VERSION 5.8 ;
BUSBITCHARS "[]" ;
DIVIDERCHAR "/" ;
UNITS
    DATABASE MICRONS 1000 ;
END UNITS

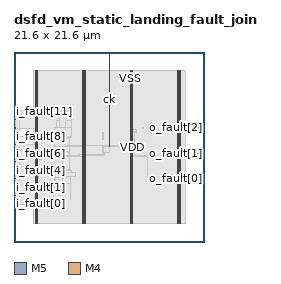
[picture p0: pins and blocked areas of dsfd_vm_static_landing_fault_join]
MACRO dsfd_vm_static_landing_fault_join
  FOREIGN dsfd_vm_static_landing_fault_join 0 0 ;
  CLASS BLOCK ;
  SIZE 21.6 BY 21.6 ;
  PIN ck
    DIRECTION INPUT ;
    USE SIGNAL ;
    PORT
      LAYER M5 ;
        RECT  10.8 21.408 10.824 21.6 ;
    END
    PORT
      LAYER M5 ;
        RECT  10.8 10.883 10.824 21.456 ;
    END
  END ck
  PIN i_fault[0]
    DIRECTION INPUT ;
    USE SIGNAL ;
    PORT
      LAYER M4 ;
        RECT  0 4.32 0.192 4.344 ;
    END
  END i_fault[0]
  PIN i_fault[10]
    DIRECTION INPUT ;
    USE SIGNAL ;
    PORT
      LAYER M4 ;
        RECT  0 13.92 0.192 13.944 ;
    END
  END i_fault[10]
  PIN i_fault[11]
    DIRECTION INPUT ;
    USE SIGNAL ;
    PORT
      LAYER M4 ;
        RECT  0 14.88 0.192 14.904 ;
    END
  END i_fault[11]
  PIN i_fault[1]
    DIRECTION INPUT ;
    USE SIGNAL ;
    PORT
      LAYER M4 ;
        RECT  0 5.28 0.192 5.304 ;
    END
  END i_fault[1]
  PIN i_fault[2]
    DIRECTION INPUT ;
    USE SIGNAL ;
    PORT
      LAYER M4 ;
        RECT  0 6.24 0.192 6.264 ;
    END
  END i_fault[2]
  PIN i_fault[3]
    DIRECTION INPUT ;
    USE SIGNAL ;
    PORT
      LAYER M4 ;
        RECT  0 7.2 0.192 7.224 ;
    END
  END i_fault[3]
  PIN i_fault[4]
    DIRECTION INPUT ;
    USE SIGNAL ;
    PORT
      LAYER M4 ;
        RECT  0 8.16 0.192 8.184 ;
    END
  END i_fault[4]
  PIN i_fault[5]
    DIRECTION INPUT ;
    USE SIGNAL ;
    PORT
      LAYER M4 ;
        RECT  0 9.12 0.192 9.144 ;
    END
  END i_fault[5]
  PIN i_fault[6]
    DIRECTION INPUT ;
    USE SIGNAL ;
    PORT
      LAYER M4 ;
        RECT  0 10.08 0.192 10.104 ;
    END
  END i_fault[6]
  PIN i_fault[7]
    DIRECTION INPUT ;
    USE SIGNAL ;
    PORT
      LAYER M4 ;
        RECT  0 11.04 0.192 11.064 ;
    END
  END i_fault[7]
  PIN i_fault[8]
    DIRECTION INPUT ;
    USE SIGNAL ;
    PORT
      LAYER M4 ;
        RECT  0 12 0.192 12.024 ;
    END
  END i_fault[8]
  PIN i_fault[9]
    DIRECTION INPUT ;
    USE SIGNAL ;
    PORT
      LAYER M4 ;
        RECT  0 12.96 0.192 12.984 ;
    END
  END i_fault[9]
  PIN o_fault[0]
    DIRECTION OUTPUT ;
    USE SIGNAL ;
    PORT
      LAYER M4 ;
        RECT  21.408 7.2 21.6 7.224 ;
    END
    PORT
      LAYER M4 ;
        RECT  20.509 7.2 21.42 7.224 ;
    END
  END o_fault[0]
  PIN o_fault[1]
    DIRECTION OUTPUT ;
    USE SIGNAL ;
    PORT
      LAYER M4 ;
        RECT  21.408 10.08 21.6 10.104 ;
    END
    PORT
      LAYER M4 ;
        RECT  20.473 10.08 21.42 10.104 ;
    END
  END o_fault[1]
  PIN o_fault[2]
    DIRECTION OUTPUT ;
    USE SIGNAL ;
    PORT
      LAYER M4 ;
        RECT  21.408 12.96 21.6 12.984 ;
    END
    PORT
      LAYER M4 ;
        RECT  20.473 12.96 21.42 12.984 ;
    END
  END o_fault[2]
  PIN VDD
    DIRECTION INOUT ;
    USE POWER ;
    PORT
      LAYER M5 ;
        RECT  18.792 2.151 18.912 19.449 ;
        RECT  13.392 2.151 13.512 19.449 ;
        RECT  7.992 2.151 8.112 19.449 ;
        RECT  2.592 2.151 2.712 19.449 ;
    END
  END VDD
  PIN VSS
    DIRECTION INOUT ;
    USE GROUND ;
    PORT
      LAYER M5 ;
        RECT  18.6 2.137 18.72 19.463 ;
        RECT  13.2 2.137 13.32 19.463 ;
        RECT  7.8 2.137 7.92 19.463 ;
        RECT  2.4 2.137 2.52 19.463 ;
    END
  END VSS
  # OT_OBS_CLOSED layer=M5 d_um=1.536 added=1
  OBS
    LAYER RVTN ;
     RECT  2.16 2.16 19.44 2.295 ;
     RECT  2.16 2.565 19.44 2.835 ;
     RECT  2.16 3.105 19.44 3.375 ;
     RECT  2.16 3.645 19.44 3.915 ;
     RECT  2.16 4.185 19.44 4.455 ;
     RECT  2.16 4.725 19.44 4.995 ;
     RECT  2.16 5.265 19.44 5.535 ;
     RECT  2.16 5.805 19.44 6.075 ;
     RECT  2.16 6.345 19.44 6.615 ;
     RECT  2.16 6.885 19.44 7.155 ;
     RECT  2.16 7.425 19.44 7.695 ;
     RECT  2.16 7.965 19.44 8.235 ;
     RECT  2.16 8.505 19.44 8.775 ;
     RECT  2.16 9.045 19.44 9.315 ;
     RECT  2.16 9.585 19.44 9.855 ;
     RECT  2.16 10.125 19.44 10.395 ;
     RECT  2.16 10.665 19.44 10.935 ;
     RECT  2.16 11.205 19.44 11.475 ;
     RECT  2.16 11.745 19.44 12.015 ;
     RECT  2.16 12.285 19.44 12.555 ;
     RECT  2.16 12.825 19.44 13.095 ;
     RECT  2.16 13.365 19.44 13.635 ;
     RECT  2.16 13.905 19.44 14.175 ;
     RECT  2.16 14.445 19.44 14.715 ;
     RECT  2.16 14.985 19.44 15.255 ;
     RECT  2.16 15.525 19.44 15.795 ;
     RECT  2.16 16.065 19.44 16.335 ;
     RECT  2.16 16.605 19.44 16.875 ;
     RECT  2.16 17.145 19.44 17.415 ;
     RECT  2.16 17.685 19.44 17.955 ;
     RECT  2.16 18.225 19.44 18.495 ;
     RECT  2.16 18.765 19.44 19.035 ;
     RECT  2.16 19.305 19.44 19.44 ;
    LAYER RVTP ;
     RECT  2.16 2.295 19.44 2.565 ;
     RECT  2.16 2.835 19.44 3.105 ;
     RECT  2.16 3.375 19.44 3.645 ;
     RECT  2.16 3.915 19.44 4.185 ;
     RECT  2.16 4.455 19.44 4.725 ;
     RECT  2.16 4.995 19.44 5.265 ;
     RECT  2.16 5.535 19.44 5.805 ;
     RECT  2.16 6.075 19.44 6.345 ;
     RECT  2.16 6.615 19.44 6.885 ;
     RECT  2.16 7.155 19.44 7.425 ;
     RECT  2.16 7.695 19.44 7.965 ;
     RECT  2.16 8.235 19.44 8.505 ;
     RECT  2.16 8.775 19.44 9.045 ;
     RECT  2.16 9.315 19.44 9.585 ;
     RECT  2.16 9.855 19.44 10.125 ;
     RECT  2.16 10.395 19.44 10.665 ;
     RECT  2.16 10.935 19.44 11.205 ;
     RECT  2.16 11.475 19.44 11.745 ;
     RECT  2.16 12.015 19.44 12.285 ;
     RECT  2.16 12.555 19.44 12.825 ;
     RECT  2.16 13.095 19.44 13.365 ;
     RECT  2.16 13.635 19.44 13.905 ;
     RECT  2.16 14.175 19.44 14.445 ;
     RECT  2.16 14.715 19.44 14.985 ;
     RECT  2.16 15.255 19.44 15.525 ;
     RECT  2.16 15.795 19.44 16.065 ;
     RECT  2.16 16.335 19.44 16.605 ;
     RECT  2.16 16.875 19.44 17.145 ;
     RECT  2.16 17.415 19.44 17.685 ;
     RECT  2.16 17.955 19.44 18.225 ;
     RECT  2.16 18.495 19.44 18.765 ;
     RECT  2.16 19.035 19.44 19.305 ;
    LAYER M1 ;
     RECT  2.16 2.151 19.44 19.449 ;
    LAYER M2 ;
     RECT  0.535 11.952 2.16 11.97 ;
     RECT  2.16 2.151 19.44 19.449 ;
     RECT  19.44 10.296 20.507 10.314 ;
     RECT  19.44 13.266 20.507 13.284 ;
     RECT  19.44 6.822 20.543 6.84 ;
    LAYER M3 ;
     RECT  2.415 2.143 2.505 2.413 ;
     RECT  7.815 2.143 7.905 2.413 ;
     RECT  13.215 2.143 13.305 2.413 ;
     RECT  18.615 2.143 18.705 2.413 ;
     RECT  2.415 2.413 2.697 4.315 ;
     RECT  2.304 4.315 2.697 4.685 ;
     RECT  2.34 4.685 2.697 5.495 ;
     RECT  4.5 4.801 4.518 5.611 ;
     RECT  3.996 5.611 4.518 5.909 ;
     RECT  4.5 5.909 4.518 6.241 ;
     RECT  5.472 5.881 5.49 6.241 ;
     RECT  4.5 6.241 5.49 6.317 ;
     RECT  5.004 6.317 5.49 6.575 ;
     RECT  5.472 6.575 5.49 6.691 ;
     RECT  6.444 4.801 6.462 6.691 ;
     RECT  18.615 2.413 18.897 6.925 ;
     RECT  2.415 5.495 2.697 7.195 ;
     RECT  20.52 6.817 20.538 7.229 ;
     RECT  7.815 2.413 8.097 7.231 ;
     RECT  18.615 6.925 19.134 7.231 ;
     RECT  16.344 7.231 16.362 7.349 ;
     RECT  18.615 7.231 19.314 7.349 ;
     RECT  2.415 7.195 2.754 7.385 ;
     RECT  16.164 7.357 16.182 7.421 ;
     RECT  5.472 6.691 6.462 7.501 ;
     RECT  17.748 7.357 17.766 7.501 ;
     RECT  18.615 7.349 18.897 7.501 ;
     RECT  17.748 7.501 18.897 7.619 ;
     RECT  17.748 7.619 17.766 7.655 ;
     RECT  5.472 7.501 7.002 7.925 ;
     RECT  2.415 7.385 2.697 8.155 ;
     RECT  5.472 7.925 6.498 8.159 ;
     RECT  7.74 7.231 8.097 8.159 ;
     RECT  5.472 8.159 6.462 8.267 ;
     RECT  2.415 8.155 2.754 8.311 ;
     RECT  2.415 8.311 2.934 8.429 ;
     RECT  4.608 8.347 4.626 8.537 ;
     RECT  2.415 8.429 2.697 9.115 ;
     RECT  2.304 9.115 2.697 9.275 ;
     RECT  2.415 9.275 2.697 9.391 ;
     RECT  2.415 9.391 3.222 9.509 ;
     RECT  3.996 9.643 4.014 9.689 ;
     RECT  5.472 8.267 6.318 9.691 ;
     RECT  7.815 8.159 8.097 9.691 ;
     RECT  15.156 9.739 15.174 9.815 ;
     RECT  5.472 9.691 6.822 9.821 ;
     RECT  7.596 9.691 8.097 9.883 ;
     RECT  7.488 9.883 8.097 9.923 ;
     RECT  18.615 7.619 18.897 10.021 ;
     RECT  10.188 9.883 10.206 10.049 ;
     RECT  16.092 9.931 16.11 10.085 ;
     RECT  18.54 10.021 18.897 10.121 ;
     RECT  5.472 9.821 6.318 10.201 ;
     RECT  18.615 10.121 18.897 10.201 ;
     RECT  10.08 10.165 10.098 10.205 ;
     RECT  5.4 10.201 6.318 10.253 ;
     RECT  20.484 10.075 20.502 10.319 ;
     RECT  18.615 10.201 19.098 10.355 ;
     RECT  13.215 2.413 13.497 10.741 ;
     RECT  5.832 10.253 6.318 10.891 ;
     RECT  11.988 10.741 13.497 10.925 ;
     RECT  5.832 10.891 6.858 10.931 ;
     RECT  5.868 10.931 6.858 11.021 ;
     RECT  11.988 10.925 12.006 11.021 ;
     RECT  5.868 11.021 6.318 11.785 ;
     RECT  5.796 11.785 6.318 11.821 ;
     RECT  5.292 11.821 6.318 11.911 ;
     RECT  5.292 11.911 6.534 11.939 ;
     RECT  4.356 11.899 4.374 11.975 ;
     RECT  0.54 11.947 0.558 12.029 ;
     RECT  10.116 11.641 10.134 12.479 ;
     RECT  13.215 10.925 13.497 12.487 ;
     RECT  13.215 12.487 13.878 12.749 ;
     RECT  2.415 9.509 2.697 12.955 ;
     RECT  18.615 10.355 18.897 12.991 ;
     RECT  5.904 11.939 6.534 13.003 ;
     RECT  2.304 12.955 2.697 13.055 ;
     RECT  5.256 13.003 6.534 13.055 ;
     RECT  14.652 12.901 14.67 13.055 ;
     RECT  18.324 12.991 18.897 13.091 ;
     RECT  18.615 13.091 18.897 13.171 ;
     RECT  20.484 12.955 20.502 13.289 ;
     RECT  18.615 13.171 19.098 13.325 ;
     RECT  5.904 13.055 6.534 13.829 ;
     RECT  4.896 13.819 4.914 13.865 ;
     RECT  6.516 13.829 6.534 14.827 ;
     RECT  6.012 14.827 6.534 14.909 ;
     RECT  6.012 14.909 6.03 14.945 ;
     RECT  2.415 13.055 2.697 19.187 ;
     RECT  7.815 9.923 8.097 19.187 ;
     RECT  13.215 12.749 13.497 19.187 ;
     RECT  18.615 13.325 18.897 19.187 ;
     RECT  2.415 19.187 2.505 19.457 ;
     RECT  7.815 19.187 7.905 19.457 ;
     RECT  13.215 19.187 13.305 19.457 ;
     RECT  18.615 19.187 18.705 19.457 ;
    LAYER M4 ;
     RECT  0.156 4.32 0.569 14.904 ;
     RECT  0.569 4.32 2.408 11.064 ;
     RECT  0.569 12.96 2.408 14.904 ;
     RECT  2.408 2.148 2.512 19.452 ;
     RECT  2.512 2.418 2.704 19.182 ;
     RECT  2.704 7.2 2.765 8.184 ;
     RECT  4.556 8.496 4.597 8.52 ;
     RECT  3.985 9.648 4.597 9.672 ;
     RECT  4.597 8.352 4.643 8.52 ;
     RECT  4.597 9.648 4.643 9.816 ;
     RECT  4.345 11.904 4.643 11.928 ;
     RECT  4.643 8.352 4.691 8.376 ;
     RECT  4.597 13.008 4.885 13.032 ;
     RECT  4.489 6.288 5.033 6.312 ;
     RECT  4.885 13.008 5.171 13.848 ;
     RECT  5.171 13.008 5.285 13.032 ;
     RECT  4.643 9.792 5.372 9.816 ;
     RECT  5.372 9.792 5.413 10.248 ;
     RECT  5.413 9.792 5.459 10.872 ;
     RECT  5.459 10.848 5.861 10.872 ;
     RECT  4.645 7.344 6.041 7.368 ;
     RECT  5.125 14.832 6.041 14.856 ;
     RECT  5.459 9.792 6.793 9.816 ;
     RECT  6.217 10.896 6.829 10.92 ;
     RECT  6.793 9.696 7.477 9.816 ;
     RECT  7.477 9.696 7.808 9.912 ;
     RECT  6.829 10.896 7.808 11.016 ;
     RECT  7.808 2.148 7.912 19.452 ;
     RECT  7.912 2.418 8.104 19.182 ;
     RECT  8.104 9.888 10.069 9.912 ;
     RECT  8.104 10.992 10.069 11.016 ;
     RECT  10.069 9.888 10.281 11.016 ;
     RECT  10.281 10.176 10.835 11.016 ;
     RECT  10.835 10.848 12.017 11.016 ;
     RECT  12.017 10.848 12.197 10.92 ;
     RECT  12.197 10.896 13.208 10.92 ;
     RECT  13.208 2.148 13.312 19.452 ;
     RECT  13.312 2.418 13.504 19.182 ;
     RECT  13.504 10.896 13.763 10.92 ;
     RECT  13.504 12.528 13.789 12.552 ;
     RECT  13.504 9.744 15.203 9.768 ;
     RECT  15.157 7.392 16.193 7.416 ;
     RECT  18.608 2.148 18.712 19.452 ;
     RECT  18.712 2.418 18.904 19.182 ;
    LAYER M5 ;
     RECT  2.4 2.137 2.52 2.151 ;
     RECT  7.8 2.137 7.92 2.151 ;
     RECT  13.2 2.137 13.32 2.151 ;
     RECT  18.6 2.137 18.72 2.151 ;
     RECT  4.656 6.277 4.68 8.387 ;
     RECT  13.2 2.151 13.512 9.733 ;
     RECT  15.168 7.381 15.192 9.779 ;
     RECT  10.224 9.877 10.248 10.165 ;
     RECT  4.608 8.485 4.632 10.213 ;
     RECT  4.608 10.213 5.448 10.883 ;
     RECT  10.224 10.165 10.824 10.883 ;
     RECT  13.2 9.733 13.752 12.563 ;
     RECT  4.608 10.883 4.632 12.997 ;
     RECT  4.608 12.997 5.16 13.043 ;
     RECT  5.136 13.043 5.16 14.867 ;
     RECT  2.4 2.151 2.712 19.449 ;
     RECT  7.8 2.151 8.112 19.449 ;
     RECT  13.2 12.563 13.512 19.449 ;
     RECT  18.6 2.151 18.912 19.449 ;
     RECT  2.4 19.449 2.52 19.463 ;
     RECT  7.8 19.449 7.92 19.463 ;
     RECT  13.2 19.449 13.32 19.463 ;
     RECT  18.6 19.449 18.72 19.463 ;
     RECT  13.752 9.733 15.168 9.779 ;
  END
END dsfd_vm_static_landing_fault_join
END LIBRARY
